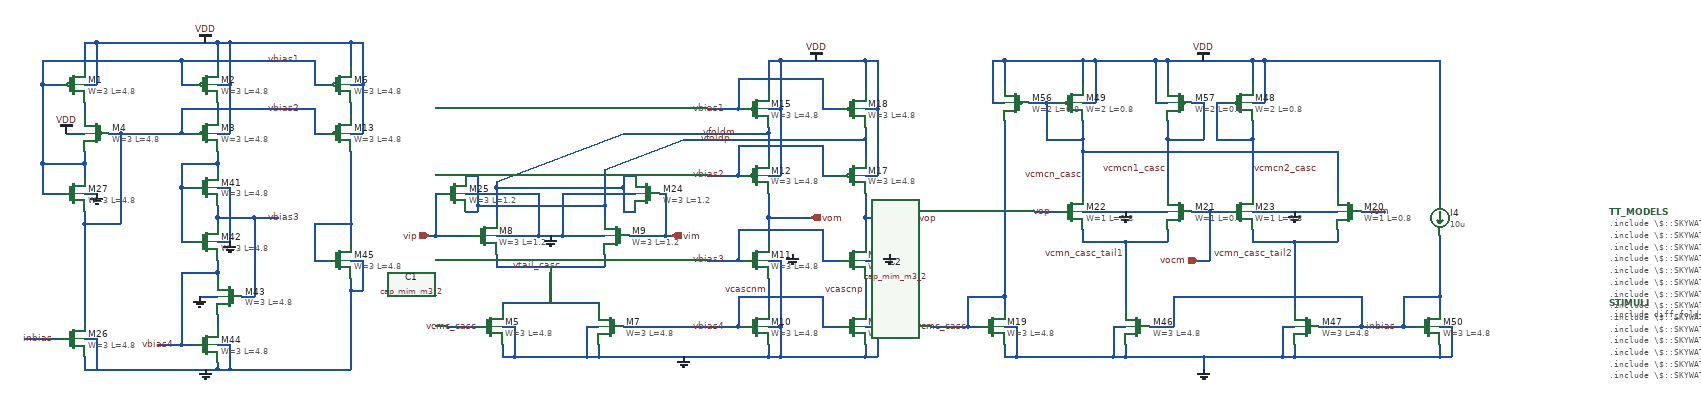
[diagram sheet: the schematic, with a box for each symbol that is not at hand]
v {xschem version=2.9.9 file_version=1.2 

* Copyright 2020 Stefan Frederik Schippers
* 
* Licensed under the Apache License, Version 2.0 (the "License");
* you may not use this file except in compliance with the License.
* You may obtain a copy of the License at
*
*     https://www.apache.org/licenses/LICENSE-2.0
*
* Unless required by applicable law or agreed to in writing, software
* distributed under the License is distributed on an "AS IS" BASIS,
* WITHOUT WARRANTIES OR CONDITIONS OF ANY KIND, either express or implied.
* See the License for the specific language governing permissions and
* limitations under the License.

}
G {}
K {}
V {}
S {}
E {}
N -510 -220 -490 -220 { lab=GND}
N -490 -220 -490 -170 { lab=GND}
N -370 -220 -350 -220 { lab=GND}
N -370 -220 -370 -170 { lab=GND}
N -510 -260 -510 -250 { lab=vtail_casc}
N -510 -260 -350 -260 { lab=vtail_casc}
N -350 -260 -350 -250 { lab=vtail_casc}
N -350 -190 -350 -170 { lab=GND}
N -510 -190 -510 -170 { lab=GND}
N -410 -370 -340 -370 { lab=GND}
N -520 -340 -520 -320 { lab=vtail_casc}
N -520 -320 -340 -320 { lab=vtail_casc}
N -340 -340 -340 -320 { lab=vtail_casc}
N -370 -170 -350 -170 { lab=GND}
N -70 -190 -70 -170 { lab=GND}
N -350 -170 -70 -170 { lab=GND}
N 90 -190 90 -170 { lab=GND}
N -50 -170 90 -170 { lab=GND}
N -70 -300 -70 -250 { lab=vcascnm}
N 90 -300 90 -250 { lab=vcascnp}
N -70 -400 -70 -360 { lab=vom}
N 90 -400 90 -360 { lab=vop}
N 90 -530 90 -500 { lab=vfoldp}
N -70 -540 -70 -500 { lab=vfoldm}
N -50 -660 90 -660 { lab=VDD}
N -70 -470 -50 -470 { lab=VDD}
N -50 -580 -50 -470 { lab=VDD}
N 90 -470 110 -470 { lab=VDD}
N 110 -580 110 -470 { lab=VDD}
N -50 -220 -50 -170 { lab=GND}
N 90 -220 110 -220 { lab=GND}
N 110 -220 110 -170 { lab=GND}
N 90 -170 110 -170 { lab=GND}
N 90 -330 110 -330 { lab=GND}
N 110 -330 110 -220 { lab=GND}
N -50 -330 -50 -220 { lab=GND}
N -120 -470 -110 -470 { lab=vbias2}
N -120 -520 -120 -470 { lab=vbias2}
N -120 -520 20 -520 { lab=vbias2}
N 20 -520 20 -470 { lab=vbias2}
N 20 -470 50 -470 { lab=vbias2}
N 90 -660 110 -660 { lab=VDD}
N 110 -660 110 -580 { lab=VDD}
N -120 -580 -110 -580 { lab=vbias1}
N -120 -630 -120 -580 { lab=vbias1}
N -120 -630 20 -630 { lab=vbias1}
N 20 -630 20 -580 { lab=vbias1}
N 20 -580 50 -580 { lab=vbias1}
N 90 -660 90 -610 { lab=VDD}
N -70 -660 -70 -610 { lab=VDD}
N -70 -330 -50 -330 { lab=GND}
N -120 -330 -110 -330 { lab=vbias3}
N -120 -380 -120 -330 { lab=vbias3}
N -120 -380 20 -380 { lab=vbias3}
N 20 -380 20 -330 { lab=vbias3}
N 20 -330 50 -330 { lab=vbias3}
N -120 -270 -120 -220 { lab=vbias4}
N -120 -270 20 -270 { lab=vbias4}
N 20 -270 20 -220 { lab=vbias4}
N 20 -220 50 -220 { lab=vbias4}
N -120 -220 -110 -220 { lab=vbias4}
N -1200 -690 -1200 -650 { lab=VDD}
N -760 -690 -760 -650 { lab=VDD}
N -980 -690 -980 -650 { lab=VDD}
N -980 -620 -960 -620 { lab=VDD}
N -960 -690 -960 -620 { lab=VDD}
N -760 -620 -740 -620 { lab=VDD}
N -740 -690 -740 -620 { lab=VDD}
N -1200 -620 -1180 -620 { lab=VDD}
N -1180 -690 -1180 -620 { lab=VDD}
N -760 -690 -740 -690 { lab=VDD}
N -980 -590 -980 -570 { lab=#net1}
N -960 -150 -760 -150 { lab=GND}
N -1270 -620 -1240 -620 { lab=vbias1}
N -1270 -440 -1240 -440 { lab=vbias1}
N -1200 -490 -1200 -470 { lab=vbias1}
N -1270 -490 -1200 -490 { lab=vbias1}
N -1270 -620 -1270 -490 { lab=vbias1}
N -1040 -540 -1020 -540 { lab=vbias2}
N -1200 -390 -1140 -390 { lab=vbias2}
N -1140 -540 -1140 -390 { lab=vbias2}
N -980 -490 -980 -480 { lab=#net2}
N -980 -400 -980 -390 { lab=vbias3}
N -980 -310 -980 -300 { lab=vbias4}
N -1040 -190 -1020 -190 { lab=vbias4}
N -920 -400 -880 -400 { lab=vbias3}
N -940 -270 -920 -270 { lab=vbias3}
N -920 -400 -920 -270 { lab=vbias3}
N -1040 -310 -1040 -190 { lab=vbias4}
N -1040 -310 -980 -310 { lab=vbias4}
N -1040 -360 -1020 -360 { lab=#net2}
N -1040 -450 -1040 -360 { lab=#net2}
N -1040 -490 -980 -490 { lab=#net2}
N -1040 -450 -1020 -450 { lab=#net2}
N -760 -590 -760 -570 { lab=#net3}
N -1040 -580 -1040 -540 { lab=vbias2}
N -760 -390 -760 -360 { lab=#net4}
N -820 -330 -800 -330 { lab=#net4}
N -820 -390 -820 -330 { lab=#net4}
N -820 -390 -760 -390 { lab=#net4}
N -1270 -660 -1270 -620 { lab=vbias1}
N -1270 -660 -1040 -660 { lab=vbias1}
N -1040 -660 -1040 -620 { lab=vbias1}
N -1040 -620 -1020 -620 { lab=vbias1}
N -1040 -660 -820 -660 { lab=vbias1}
N -820 -660 -820 -620 { lab=vbias1}
N -820 -620 -800 -620 { lab=vbias1}
N -1040 -580 -820 -580 { lab=vbias2}
N -820 -580 -820 -540 { lab=vbias2}
N -820 -540 -800 -540 { lab=vbias2}
N -1200 -590 -1200 -570 { lab=#net5}
N -980 -160 -980 -150 { lab=GND}
N -980 -190 -960 -190 { lab=GND}
N -960 -190 -960 -150 { lab=GND}
N -760 -540 -740 -540 { lab=VDD}
N -740 -620 -740 -540 { lab=VDD}
N -760 -330 -740 -330 { lab=GND}
N -740 -330 -740 -280 { lab=GND}
N -760 -280 -740 -280 { lab=GND}
N -1010 -270 -980 -270 { lab=GND}
N -980 -450 -960 -450 { lab=GND}
N -960 -450 -960 -360 { lab=GND}
N -980 -360 -960 -360 { lab=GND}
N -980 -540 -960 -540 { lab=VDD}
N -960 -620 -960 -540 { lab=VDD}
N -1230 -540 -1200 -540 { lab=VDD}
N -50 -660 -50 -580 { lab=VDD}
N -70 -220 -50 -220 { lab=GND}
N -70 -580 -50 -580 { lab=VDD}
N 90 -580 110 -580 { lab=VDD}
N 660 -410 690 -410 { lab=vocm}
N 520 -190 520 -170 { lab=GND}
N 780 -170 800 -170 { lab=GND}
N 800 -190 800 -170 { lab=GND}
N 650 -170 650 -150 { lab=GND}
N 450 -380 450 -360 { lab=vcmn_casc_tail1}
N 520 -360 590 -360 { lab=vcmn_casc_tail1}
N 590 -380 590 -360 { lab=vcmn_casc_tail1}
N 730 -380 730 -360 { lab=vcmn_casc_tail2}
N 800 -360 870 -360 { lab=vcmn_casc_tail2}
N 870 -380 870 -360 { lab=vcmn_casc_tail2}
N 670 -590 690 -590 { lab=vcmcn2_casc}
N 670 -590 670 -530 { lab=vcmcn2_casc}
N 670 -530 730 -530 { lab=vcmcn2_casc}
N 390 -590 410 -590 { lab=vcmcn_casc}
N 390 -590 390 -530 { lab=vcmcn_casc}
N 390 -530 450 -530 { lab=vcmcn_casc}
N 450 -510 450 -440 { lab=vcmcn_casc}
N 450 -590 470 -590 { lab=VDD}
N 730 -590 750 -590 { lab=VDD}
N 450 -410 590 -410 { lab=GND}
N 730 -410 870 -410 { lab=GND}
N 780 -220 800 -220 { lab=GND}
N 780 -220 780 -170 { lab=GND}
N 500 -220 520 -220 { lab=GND}
N 500 -220 500 -170 { lab=GND}
N 500 -170 520 -170 { lab=GND}
N 1040 -190 1040 -170 { lab=GND}
N 980 -270 1040 -270 { lab=vnbias_diff_ota}
N 980 -270 980 -220 { lab=vnbias_diff_ota}
N 1040 -220 1060 -220 { lab=GND}
N 1060 -220 1060 -170 { lab=GND}
N 1040 -170 1060 -170 { lab=GND}
N 980 -220 1000 -220 { lab=vnbias_diff_ota}
N 560 -220 600 -220 { lab=vnbias_diff_ota}
N 600 -270 600 -220 { lab=vnbias_diff_ota}
N 600 -270 910 -270 { lab=vnbias_diff_ota}
N 910 -270 910 -220 { lab=vnbias_diff_ota}
N 910 -410 950 -410 { lab=vom}
N 1040 -660 1040 -430 { lab=VDD}
N 750 -660 750 -590 { lab=VDD}
N 730 -660 730 -620 { lab=VDD}
N 470 -660 470 -590 { lab=VDD}
N 450 -660 450 -620 { lab=VDD}
N 1040 -270 1040 -250 { lab=vnbias_diff_ota}
N 800 -360 800 -250 { lab=vcmn_casc_tail2}
N 520 -360 520 -250 { lab=vcmn_casc_tail1}
N 320 -190 320 -170 { lab=GND}
N 260 -270 320 -270 { lab=vcmc_casc}
N 260 -270 260 -220 { lab=vcmc_casc}
N 320 -220 340 -220 { lab=GND}
N 340 -220 340 -170 { lab=GND}
N 300 -590 320 -590 { lab=VDD}
N 320 -660 320 -620 { lab=VDD}
N 300 -660 300 -590 { lab=VDD}
N 630 -590 650 -590 { lab=vcmcn1_casc}
N 650 -590 650 -530 { lab=vcmcn1_casc}
N 590 -530 650 -530 { lab=vcmcn1_casc}
N 570 -590 590 -590 { lab=VDD}
N 570 -660 570 -590 { lab=VDD}
N 590 -660 590 -620 { lab=VDD}
N 260 -220 280 -220 { lab=vcmc_casc}
N 750 -660 1040 -660 { lab=VDD}
N 340 -170 500 -170 { lab=GND}
N 200 -220 260 -220 { lab=vcmc_casc}
N 320 -270 320 -250 { lab=vcmc_casc}
N 360 -590 390 -590 { lab=vcmcn_casc}
N 730 -530 730 -440 { lab=vcmcn2_casc}
N 590 -530 590 -440 { lab=vcmcn1_casc}
N 870 -510 870 -440 { lab=vcmcn_casc}
N 450 -510 870 -510 { lab=vcmcn_casc}
N -570 -470 -550 -470 { lab=vfoldp}
N -550 -420 -550 -410 { lab=vfoldp}
N -570 -410 -550 -410 { lab=vfoldp}
N -310 -470 -290 -470 { lab=vfoldm}
N -310 -450 -310 -410 { lab=vfoldm}
N -310 -410 -290 -410 { lab=vfoldm}
N -410 -440 -290 -440 { lab=GND}
N -410 -440 -410 -370 { lab=GND}
N -570 -440 -450 -440 { lab=GND}
N -450 -440 -450 -370 { lab=GND}
N -550 -420 -340 -420 { lab=vfoldp}
N -600 -220 -550 -220 { lab=vcmc_casc}
N -300 -370 -240 -370 { lab=vim}
N -240 -440 -240 -370 { lab=vim}
N -250 -440 -240 -440 { lab=vim}
N -620 -370 -560 -370 { lab=vip}
N -620 -440 -620 -370 { lab=vip}
N -620 -440 -610 -440 { lab=vip}
N -630 -370 -620 -370 { lab=vip}
N -240 -370 -230 -370 { lab=vim}
N 640 -330 660 -330 { lab=vocm}
N 660 -410 660 -330 { lab=vocm}
N -340 -420 -340 -400 { lab=vfoldp}
N -210 -530 90 -530 { lab=vfoldp}
N -520 -450 -520 -400 { lab=vfoldm}
N -340 -480 -210 -530 { lab=vfoldp}
N -490 -170 -370 -170 { lab=GND}
N -510 -170 -490 -170 { lab=GND}
N -70 -170 -50 -170 { lab=GND}
N -170 -470 -120 -470 { lab=vbias2}
N -170 -580 -120 -580 { lab=vbias1}
N -170 -330 -120 -330 { lab=vbias3}
N -310 -220 -120 -220 { lab=vbias4}
N -960 -690 -760 -690 { lab=VDD}
N -1180 -690 -980 -690 { lab=VDD}
N -980 -690 -960 -690 { lab=VDD}
N -1200 -690 -1180 -690 { lab=VDD}
N -1200 -510 -1200 -490 { lab=vbias1}
N -1200 -410 -1200 -390 { lab=vbias2}
N -1160 -540 -1140 -540 { lab=vbias2}
N -980 -420 -980 -400 { lab=vbias3}
N -980 -400 -920 -400 { lab=vbias3}
N -1080 -190 -1040 -190 { lab=vbias4}
N -980 -330 -980 -310 { lab=vbias4}
N -980 -510 -980 -490 { lab=#net2}
N -1040 -490 -1040 -450 { lab=#net2}
N -1140 -540 -1040 -540 { lab=vbias2}
N -760 -510 -760 -390 { lab=#net4}
N -1200 -150 -980 -150 { lab=GND}
N -980 -150 -960 -150 { lab=GND}
N -760 -300 -760 -280 { lab=GND}
N -70 -660 -50 -660 { lab=VDD}
N 520 -170 650 -170 { lab=GND}
N 730 -560 730 -530 { lab=vcmcn2_casc}
N 450 -560 450 -530 { lab=vcmcn_casc}
N 650 -170 780 -170 { lab=GND}
N 800 -170 1040 -170 { lab=GND}
N 1040 -370 1040 -270 { lab=vnbias_diff_ota}
N 910 -220 980 -220 { lab=vnbias_diff_ota}
N 840 -220 910 -220 { lab=vnbias_diff_ota}
N 730 -660 750 -660 { lab=VDD}
N 590 -660 730 -660 { lab=VDD}
N 450 -660 470 -660 { lab=VDD}
N 320 -660 450 -660 { lab=VDD}
N 730 -360 800 -360 { lab=vcmn_casc_tail2}
N 450 -360 520 -360 { lab=vcmn_casc_tail1}
N 320 -170 340 -170 { lab=GND}
N 300 -660 320 -660 { lab=VDD}
N 590 -560 590 -530 { lab=vcmcn1_casc}
N 470 -660 570 -660 { lab=VDD}
N 570 -660 590 -660 { lab=VDD}
N 450 -530 450 -510 { lab=vcmcn_casc}
N -450 -370 -410 -370 { lab=GND}
N -520 -370 -450 -370 { lab=GND}
N -310 -470 -310 -450 { lab=vfoldm}
N -550 -470 -550 -420 { lab=vfoldp}
N -340 -480 -340 -420 { lab=vfoldp}
N 90 -440 90 -400 { lab=vop}
N -70 -440 -70 -400 { lab=vom}
N 630 -410 660 -410 { lab=vocm}
N 90 -550 90 -530 { lab=vfoldp}
N -70 -550 -70 -540 { lab=vfoldm}
N -520 -450 -310 -450 { lab=vfoldm}
N -520 -460 -520 -450 { lab=vfoldm}
N -520 -460 -310 -540 { lab=vfoldm}
N -310 -540 -70 -540 { lab=vfoldm}
N -70 -400 -0 -400 { lab=vom}
N 370 -410 410 -410 { lab=vop}
N 320 -560 320 -270 { lab=vcmc_casc}
N -430 -320 -430 -260 { lab=vtail_casc}
N -760 -280 -760 -150 { lab=GND}
N -980 -240 -980 -220 { lab=#net6}
N -1200 -170 -1200 -150 { lab=GND}
N -1200 -200 -1190 -200 { lab=GND}
N -1190 -200 -1180 -200 { lab=GND}
N -1180 -200 -1180 -150 { lab=GND}
N -1200 -300 -1200 -230 { lab=vbias2}
N -1200 -390 -1200 -360 { lab=vbias2}
N -1200 -440 -1180 -440 { lab=GND}
N -1270 -490 -1270 -440 { lab=vbias1}
N -1200 -360 -1200 -300 { lab=vbias2}
N 90 -400 160 -400 { lab=vop}
N -1300 -200 -1240 -200 { lab=inbias}
C {devices/title.sym} 160 -30 0 0 {name=l1 author="Nikhil Poole"}
C {devices/code.sym} 1320 -260 0 0 {name=STIMULI 
only_toplevel=true
place=end
value=".include diff_fold_casc_ota_final_commands.spice"}
C {devices/code.sym} 1320 -410 0 0 {name=TT_MODELS
only_toplevel=true
format="tcleval( @value )"
value="
.include \\\\$::SKYWATER_MODELS\\\\/cells/nfet_01v8/sky130_fd_pr__nfet_01v8__tt.corner.spice
.include \\\\$::SKYWATER_MODELS\\\\/cells/nfet_01v8_lvt/sky130_fd_pr__nfet_01v8_lvt__tt.corner.spice
.include \\\\$::SKYWATER_MODELS\\\\/cells/pfet_01v8/sky130_fd_pr__pfet_01v8__tt.corner.spice
.include \\\\$::SKYWATER_MODELS\\\\/cells/nfet_03v3_nvt/sky130_fd_pr__nfet_03v3_nvt__tt.corner.spice
.include \\\\$::SKYWATER_MODELS\\\\/cells/nfet_05v0_nvt/sky130_fd_pr__nfet_05v0_nvt__tt.corner.spice
.include \\\\$::SKYWATER_MODELS\\\\/cells/esd_nfet_01v8/sky130_fd_pr__esd_nfet_01v8__tt.corner.spice
.include \\\\$::SKYWATER_MODELS\\\\/cells/pfet_01v8_lvt/sky130_fd_pr__pfet_01v8_lvt__tt.corner.spice
.include \\\\$::SKYWATER_MODELS\\\\/cells/pfet_01v8_hvt/sky130_fd_pr__pfet_01v8_hvt__tt.corner.spice
.include \\\\$::SKYWATER_MODELS\\\\/cells/esd_pfet_g5v0d10v5/sky130_fd_pr__esd_pfet_g5v0d10v5__tt.corner.spice
.include \\\\$::SKYWATER_MODELS\\\\/cells/pfet_g5v0d10v5/sky130_fd_pr__pfet_g5v0d10v5__tt.corner.spice
.include \\\\$::SKYWATER_MODELS\\\\/cells/pfet_g5v0d16v0/sky130_fd_pr__pfet_g5v0d16v0__tt.corner.spice
.include \\\\$::SKYWATER_MODELS\\\\/cells/nfet_g5v0d10v5/sky130_fd_pr__nfet_g5v0d10v5__tt.corner.spice
.include \\\\$::SKYWATER_MODELS\\\\/cells/nfet_g5v0d16v0/sky130_fd_pr__nfet_g5v0d16v0__tt_discrete.corner.spice
.include \\\\$::SKYWATER_MODELS\\\\/cells/esd_nfet_g5v0d10v5/sky130_fd_pr__esd_nfet_g5v0d10v5__tt.corner.spice
.include \\\\$::SKYWATER_MODELS\\\\/models/corners/tt/nonfet.spice
* Mismatch parameters
.include \\\\$::SKYWATER_MODELS\\\\/cells/nfet_01v8/sky130_fd_pr__nfet_01v8__mismatch.corner.spice
.include \\\\$::SKYWATER_MODELS\\\\/cells/pfet_01v8/sky130_fd_pr__pfet_01v8__mismatch.corner.spice
.include \\\\$::SKYWATER_MODELS\\\\/cells/nfet_01v8_lvt/sky130_fd_pr__nfet_01v8_lvt__mismatch.corner.spice
.include \\\\$::SKYWATER_MODELS\\\\/cells/pfet_01v8_lvt/sky130_fd_pr__pfet_01v8_lvt__mismatch.corner.spice
.include \\\\$::SKYWATER_MODELS\\\\/cells/pfet_01v8_hvt/sky130_fd_pr__pfet_01v8_hvt__mismatch.corner.spice
.include \\\\$::SKYWATER_MODELS\\\\/cells/nfet_g5v0d10v5/sky130_fd_pr__nfet_g5v0d10v5__mismatch.corner.spice
.include \\\\$::SKYWATER_MODELS\\\\/cells/pfet_g5v0d10v5/sky130_fd_pr__pfet_g5v0d10v5__mismatch.corner.spice
.include \\\\$::SKYWATER_MODELS\\\\/cells/nfet_05v0_nvt/sky130_fd_pr__nfet_05v0_nvt__mismatch.corner.spice
.include \\\\$::SKYWATER_MODELS\\\\/cells/nfet_03v3_nvt/sky130_fd_pr__nfet_03v3_nvt__mismatch.corner.spice
* Resistor\\\\$::SKYWATER_MODELS\\\\/Capacitor
.include \\\\$::SKYWATER_MODELS\\\\/models/r+c/res_typical__cap_typical.spice
.include \\\\$::SKYWATER_MODELS\\\\/models/r+c/res_typical__cap_typical__lin.spice
* Special cells
.include \\\\$::SKYWATER_MODELS\\\\/models/corners/tt/specialized_cells.spice
* All models
.include \\\\$::SKYWATER_MODELS\\\\/models/all.spice
* Corner
.include \\\\$::SKYWATER_MODELS\\\\/models/corners/tt/rf.spice
"}
C {devices/gnd.sym} -430 -370 0 0 {name=l12 lab=GND}
C {devices/lab_wire.sym} -410 -320 0 0 {name=l17 sig_type=std_logic lab=vtail_casc}
C {devices/lab_wire.sym} -550 -220 0 0 {name=l20 sig_type=std_logic lab=vcmc_casc}
C {devices/gnd.sym} -210 -170 0 0 {name=l19 lab=GND}
C {devices/lab_wire.sym} -140 -470 0 0 {name=l21 sig_type=std_logic lab=vbias2}
C {devices/lab_wire.sym} -140 -580 0 0 {name=l22 sig_type=std_logic lab=vbias1}
C {devices/lab_wire.sym} -140 -330 0 0 {name=l24 sig_type=std_logic lab=vbias3}
C {devices/lab_wire.sym} -140 -220 0 0 {name=l25 sig_type=std_logic lab=vbias4}
C {sky130_fd_pr/nfet_01v8.sym} -1000 -450 0 0 {name=M41
L=4.8
W=3
nf=1 
mult=50
ad="'int((nf+1)/2) * W/nf * 0.29'" 
pd="'2*int((nf+1)/2) * (W/nf + 0.29)'"
as="'int((nf+2)/2) * W/nf * 0.29'" 
ps="'2*int((nf+2)/2) * (W/nf + 0.29)'"
nrd="'0.29 / W'" nrs="'0.29 / W'"
sa=0 sb=0 sd=0
model=nfet_01v8
spiceprefix=X
}
C {sky130_fd_pr/nfet_01v8.sym} -1000 -360 0 0 {name=M42
L=4.8
W=3
nf=1 
mult=2
ad="'int((nf+1)/2) * W/nf * 0.29'" 
pd="'2*int((nf+1)/2) * (W/nf + 0.29)'"
as="'int((nf+2)/2) * W/nf * 0.29'" 
ps="'2*int((nf+2)/2) * (W/nf + 0.29)'"
nrd="'0.29 / W'" nrs="'0.29 / W'"
sa=0 sb=0 sd=0
model=nfet_01v8
spiceprefix=X
}
C {sky130_fd_pr/nfet_01v8.sym} -960 -270 0 1 {name=M43
L=4.8
W=3
nf=1 
mult=18
ad="'int((nf+1)/2) * W/nf * 0.29'" 
pd="'2*int((nf+1)/2) * (W/nf + 0.29)'"
as="'int((nf+2)/2) * W/nf * 0.29'" 
ps="'2*int((nf+2)/2) * (W/nf + 0.29)'"
nrd="'0.29 / W'" nrs="'0.29 / W'"
sa=0 sb=0 sd=0
model=nfet_01v8
spiceprefix=X
}
C {sky130_fd_pr/nfet_01v8.sym} -1000 -190 0 0 {name=M44
L=4.8
W=3
nf=1 
mult=18
ad="'int((nf+1)/2) * W/nf * 0.29'" 
pd="'2*int((nf+1)/2) * (W/nf + 0.29)'"
as="'int((nf+2)/2) * W/nf * 0.29'" 
ps="'2*int((nf+2)/2) * (W/nf + 0.29)'"
nrd="'0.29 / W'" nrs="'0.29 / W'"
sa=0 sb=0 sd=0
model=nfet_01v8
spiceprefix=X
}
C {sky130_fd_pr/nfet_01v8.sym} -780 -330 0 0 {name=M45
L=4.8
W=3
nf=1
mult=1
ad="'int((nf+1)/2) * W/nf * 0.29'" 
pd="'2*int((nf+1)/2) * (W/nf + 0.29)'"
as="'int((nf+2)/2) * W/nf * 0.29'" 
ps="'2*int((nf+2)/2) * (W/nf + 0.29)'"
nrd="'0.29 / W'" nrs="'0.29 / W'"
sa=0 sb=0 sd=0
model=nfet_01v8
spiceprefix=X
}
C {devices/lab_wire.sym} -1050 -190 0 0 {name=l33 sig_type=std_logic lab=vbias4}
C {devices/lab_wire.sym} -900 -400 0 1 {name=l36 sig_type=std_logic lab=vbias3}
C {devices/lab_wire.sym} -900 -580 0 1 {name=l37 sig_type=std_logic lab=vbias2}
C {devices/lab_wire.sym} -900 -660 0 1 {name=l41 sig_type=std_logic lab=vbias1}
C {devices/gnd.sym} -1010 -270 0 0 {name=l42 lab=GND}
C {devices/gnd.sym} -960 -360 0 0 {name=l43 lab=GND}
C {devices/vdd.sym} -1000 -690 0 0 {name=l45 lab=VDD}
C {devices/gnd.sym} -1000 -150 0 0 {name=l46 lab=GND}
C {devices/vdd.sym} -1230 -540 0 0 {name=l47 lab=VDD}
C {devices/vdd.sym} 10 -660 0 0 {name=l48 lab=VDD}
C {devices/lab_wire.sym} -180 -540 0 1 {name=l55 sig_type=std_logic lab=vfoldm}
C {devices/lab_wire.sym} -130 -530 2 1 {name=l56 sig_type=std_logic lab=vfoldp}
C {devices/lab_wire.sym} -70 -280 0 0 {name=l57 sig_type=std_logic lab=vcascnm}
C {devices/lab_wire.sym} 90 -280 0 0 {name=l58 sig_type=std_logic lab=vcascnp}
C {sky130_fd_pr/nfet_01v8.sym} 540 -220 0 1 {name=M46
L=4.8
W=3
nf=1 
mult=4
ad="'int((nf+1)/2) * W/nf * 0.29'" 
pd="'2*int((nf+1)/2) * (W/nf + 0.29)'"
as="'int((nf+2)/2) * W/nf * 0.29'" 
ps="'2*int((nf+2)/2) * (W/nf + 0.29)'"
nrd="'0.29 / W'" nrs="'0.29 / W'"
sa=0 sb=0 sd=0
model=nfet_01v8
spiceprefix=X
}
C {sky130_fd_pr/nfet_01v8.sym} 820 -220 0 1 {name=M47
L=4.8
W=3
nf=1 
mult=4
ad="'int((nf+1)/2) * W/nf * 0.29'" 
pd="'2*int((nf+1)/2) * (W/nf + 0.29)'"
as="'int((nf+2)/2) * W/nf * 0.29'" 
ps="'2*int((nf+2)/2) * (W/nf + 0.29)'"
nrd="'0.29 / W'" nrs="'0.29 / W'"
sa=0 sb=0 sd=0
model=nfet_01v8
spiceprefix=X
}
C {devices/gnd.sym} 650 -150 0 0 {name=l60 lab=GND}
C {sky130_fd_pr/pfet_01v8.sym} 710 -590 0 0 {name=M48
L=0.8
W=2
nf=1
mult=8
ad="'int((nf+1)/2) * W/nf * 0.29'" 
pd="'2*int((nf+1)/2) * (W/nf + 0.29)'"
as="'int((nf+2)/2) * W/nf * 0.29'" 
ps="'2*int((nf+2)/2) * (W/nf + 0.29)'"
nrd="'0.29 / W'" nrs="'0.29 / W'"
sa=0 sb=0 sd=0
model=pfet_01v8
spiceprefix=X
}
C {sky130_fd_pr/pfet_01v8.sym} 430 -590 0 0 {name=M49
L=0.8
W=2
nf=1
mult=8
ad="'int((nf+1)/2) * W/nf * 0.29'" 
pd="'2*int((nf+1)/2) * (W/nf + 0.29)'"
as="'int((nf+2)/2) * W/nf * 0.29'" 
ps="'2*int((nf+2)/2) * (W/nf + 0.29)'"
nrd="'0.29 / W'" nrs="'0.29 / W'"
sa=0 sb=0 sd=0
model=pfet_01v8
spiceprefix=X
}
C {devices/gnd.sym} 800 -410 0 0 {name=l61 lab=GND}
C {devices/gnd.sym} 520 -410 0 0 {name=l62 lab=GND}
C {devices/isource.sym} 1040 -400 0 1 {name=I4 value=10u}
C {sky130_fd_pr/nfet_01v8.sym} 1020 -220 0 0 {name=M50
L=4.8
W=3
nf=1 
mult=4
ad="'int((nf+1)/2) * W/nf * 0.29'" 
pd="'2*int((nf+1)/2) * (W/nf + 0.29)'"
as="'int((nf+2)/2) * W/nf * 0.29'" 
ps="'2*int((nf+2)/2) * (W/nf + 0.29)'"
nrd="'0.29 / W'" nrs="'0.29 / W'"
sa=0 sb=0 sd=0
model=nfet_01v8
spiceprefix=X
}
C {devices/lab_wire.sym} 970 -220 0 0 {name=l63 sig_type=std_logic lab=inbias}
C {devices/lab_wire.sym} 590 -480 0 0 {name=l64 sig_type=std_logic lab=vcmcn1_casc}
C {devices/lab_wire.sym} 450 -470 0 0 {name=l65 sig_type=std_logic lab=vcmcn_casc}
C {devices/lab_wire.sym} 520 -340 0 0 {name=l66 sig_type=std_logic lab=vcmn_casc_tail1}
C {devices/lab_wire.sym} 800 -340 0 0 {name=l67 sig_type=std_logic lab=vcmn_casc_tail2}
C {sky130_fd_pr/pfet_01v8.sym} 340 -590 0 1 {name=M56
L=0.8
W=2
nf=1
mult=8
ad="'int((nf+1)/2) * W/nf * 0.29'" 
pd="'2*int((nf+1)/2) * (W/nf + 0.29)'"
as="'int((nf+2)/2) * W/nf * 0.29'" 
ps="'2*int((nf+2)/2) * (W/nf + 0.29)'"
nrd="'0.29 / W'" nrs="'0.29 / W'"
sa=0 sb=0 sd=0
model=pfet_01v8
spiceprefix=X
}
C {sky130_fd_pr/pfet_01v8.sym} 610 -590 0 1 {name=M57
L=0.8
W=2
nf=1
mult=8
ad="'int((nf+1)/2) * W/nf * 0.29'" 
pd="'2*int((nf+1)/2) * (W/nf + 0.29)'"
as="'int((nf+2)/2) * W/nf * 0.29'" 
ps="'2*int((nf+2)/2) * (W/nf + 0.29)'"
nrd="'0.29 / W'" nrs="'0.29 / W'"
sa=0 sb=0 sd=0
model=pfet_01v8
spiceprefix=X
}
C {devices/lab_wire.sym} 730 -480 0 1 {name=l68 sig_type=std_logic lab=vcmcn2_casc}
C {devices/vdd.sym} 650 -660 0 0 {name=l69 lab=VDD}
C {devices/lab_wire.sym} 260 -220 0 0 {name=l70 sig_type=std_logic lab=vcmc_casc}
C {devices/lab_wire.sym} 400 -410 0 0 {name=l71 sig_type=std_logic lab=vop}
C {devices/lab_wire.sym} 920 -410 0 1 {name=l72 sig_type=std_logic lab=vom}
C {sky130_fd_pr/pfet_01v8_lvt.sym} -1220 -620 0 0 {name=M1
L=4.8
W=3
nf=1
mult=6
ad="'int((nf+1)/2) * W/nf * 0.29'" 
pd="'2*int((nf+1)/2) * (W/nf + 0.29)'"
as="'int((nf+2)/2) * W/nf * 0.29'" 
ps="'2*int((nf+2)/2) * (W/nf + 0.29)'"
nrd="'0.29 / W'" nrs="'0.29 / W'"
sa=0 sb=0 sd=0
model=pfet_01v8_lvt
spiceprefix=X
}
C {sky130_fd_pr/nfet_01v8.sym} -530 -220 0 0 {name=M5
L=4.8
W=3
nf=1
mult=18
ad="'int((nf+1)/2) * W/nf * 0.29'" 
pd="'2*int((nf+1)/2) * (W/nf + 0.29)'"
as="'int((nf+2)/2) * W/nf * 0.29'" 
ps="'2*int((nf+2)/2) * (W/nf + 0.29)'"
nrd="'0.29 / W'" nrs="'0.29 / W'"
sa=0 sb=0 sd=0
model=nfet_01v8
spiceprefix=X
}
C {devices/opin.sym} 160 -400 0 0 {name=p1 lab=vop}
C {devices/opin.sym} 0 -400 0 0 {name=p2 lab=vom}
C {devices/ipin.sym} -630 -370 0 0 {name=p3 lab=vip}
C {devices/ipin.sym} -230 -370 0 1 {name=p4 lab=vim}
C {devices/ipin.sym} 640 -330 0 0 {name=p5 lab=vocm}
C {sky130_fd_pr/nfet_01v8_lvt.sym} -540 -370 0 0 {name=M8
L=1.2
W=3
nf=1
mult=18
ad="'int((nf+1)/2) * W/nf * 0.29'" 
pd="'2*int((nf+1)/2) * (W/nf + 0.29)'"
as="'int((nf+2)/2) * W/nf * 0.29'" 
ps="'2*int((nf+2)/2) * (W/nf + 0.29)'"
nrd="'0.29 / W'" nrs="'0.29 / W'"
sa=0 sb=0 sd=0
model=nfet_01v8_lvt
spiceprefix=X
}
C {sky130_fd_pr/pfet_01v8.sym} -1000 -540 0 0 {name=M3
L=4.8
W=3
nf=1
mult=6
ad="'int((nf+1)/2) * W/nf * 0.29'" 
pd="'2*int((nf+1)/2) * (W/nf + 0.29)'"
as="'int((nf+2)/2) * W/nf * 0.29'" 
ps="'2*int((nf+2)/2) * (W/nf + 0.29)'"
nrd="'0.29 / W'" nrs="'0.29 / W'"
sa=0 sb=0 sd=0
model=pfet_01v8
spiceprefix=X
}
C {sky130_fd_pr/pfet_01v8_lvt.sym} -1000 -620 0 0 {name=M2
L=4.8
W=3
nf=1
mult=6
ad="'int((nf+1)/2) * W/nf * 0.29'" 
pd="'2*int((nf+1)/2) * (W/nf + 0.29)'"
as="'int((nf+2)/2) * W/nf * 0.29'" 
ps="'2*int((nf+2)/2) * (W/nf + 0.29)'"
nrd="'0.29 / W'" nrs="'0.29 / W'"
sa=0 sb=0 sd=0
model=pfet_01v8_lvt
spiceprefix=X
}
C {sky130_fd_pr/pfet_01v8_lvt.sym} -780 -620 0 0 {name=M6
L=4.8
W=3
nf=1
mult=6
ad="'int((nf+1)/2) * W/nf * 0.29'" 
pd="'2*int((nf+1)/2) * (W/nf + 0.29)'"
as="'int((nf+2)/2) * W/nf * 0.29'" 
ps="'2*int((nf+2)/2) * (W/nf + 0.29)'"
nrd="'0.29 / W'" nrs="'0.29 / W'"
sa=0 sb=0 sd=0
model=pfet_01v8_lvt
spiceprefix=X
}
C {sky130_fd_pr/pfet_01v8.sym} -1180 -540 0 1 {name=M4
L=4.8
W=3
nf=1
mult=6
ad="'int((nf+1)/2) * W/nf * 0.29'" 
pd="'2*int((nf+1)/2) * (W/nf + 0.29)'"
as="'int((nf+2)/2) * W/nf * 0.29'" 
ps="'2*int((nf+2)/2) * (W/nf + 0.29)'"
nrd="'0.29 / W'" nrs="'0.29 / W'"
sa=0 sb=0 sd=0
model=pfet_01v8
spiceprefix=X
}
C {sky130_fd_pr/pfet_01v8.sym} -780 -540 0 0 {name=M13
L=4.8
W=3
nf=1
mult=6
ad="'int((nf+1)/2) * W/nf * 0.29'" 
pd="'2*int((nf+1)/2) * (W/nf + 0.29)'"
as="'int((nf+2)/2) * W/nf * 0.29'" 
ps="'2*int((nf+2)/2) * (W/nf + 0.29)'"
nrd="'0.29 / W'" nrs="'0.29 / W'"
sa=0 sb=0 sd=0
model=pfet_01v8
spiceprefix=X
}
C {sky130_fd_pr/nfet_01v8.sym} -330 -220 0 1 {name=M7
L=4.8
W=3
nf=1
mult=18
ad="'int((nf+1)/2) * W/nf * 0.29'" 
pd="'2*int((nf+1)/2) * (W/nf + 0.29)'"
as="'int((nf+2)/2) * W/nf * 0.29'" 
ps="'2*int((nf+2)/2) * (W/nf + 0.29)'"
nrd="'0.29 / W'" nrs="'0.29 / W'"
sa=0 sb=0 sd=0
model=nfet_01v8
spiceprefix=X
}
C {sky130_fd_pr/nfet_01v8.sym} -90 -220 0 0 {name=M10
L=4.8
W=3
nf=1
mult=18
ad="'int((nf+1)/2) * W/nf * 0.29'" 
pd="'2*int((nf+1)/2) * (W/nf + 0.29)'"
as="'int((nf+2)/2) * W/nf * 0.29'" 
ps="'2*int((nf+2)/2) * (W/nf + 0.29)'"
nrd="'0.29 / W'" nrs="'0.29 / W'"
sa=0 sb=0 sd=0
model=nfet_01v8
spiceprefix=X
}
C {sky130_fd_pr/nfet_01v8.sym} 70 -220 0 0 {name=M14
L=4.8
W=3
nf=1
mult=18
ad="'int((nf+1)/2) * W/nf * 0.29'" 
pd="'2*int((nf+1)/2) * (W/nf + 0.29)'"
as="'int((nf+2)/2) * W/nf * 0.29'" 
ps="'2*int((nf+2)/2) * (W/nf + 0.29)'"
nrd="'0.29 / W'" nrs="'0.29 / W'"
sa=0 sb=0 sd=0
model=nfet_01v8
spiceprefix=X
}
C {sky130_fd_pr/nfet_01v8.sym} -90 -330 0 0 {name=M11
L=4.8
W=3
nf=1
mult=18
ad="'int((nf+1)/2) * W/nf * 0.29'" 
pd="'2*int((nf+1)/2) * (W/nf + 0.29)'"
as="'int((nf+2)/2) * W/nf * 0.29'" 
ps="'2*int((nf+2)/2) * (W/nf + 0.29)'"
nrd="'0.29 / W'" nrs="'0.29 / W'"
sa=0 sb=0 sd=0
model=nfet_01v8
spiceprefix=X
}
C {sky130_fd_pr/nfet_01v8.sym} 70 -330 0 0 {name=M16
L=4.8
W=3
nf=1
mult=18
ad="'int((nf+1)/2) * W/nf * 0.29'" 
pd="'2*int((nf+1)/2) * (W/nf + 0.29)'"
as="'int((nf+2)/2) * W/nf * 0.29'" 
ps="'2*int((nf+2)/2) * (W/nf + 0.29)'"
nrd="'0.29 / W'" nrs="'0.29 / W'"
sa=0 sb=0 sd=0
model=nfet_01v8
spiceprefix=X
}
C {sky130_fd_pr/pfet_01v8.sym} -90 -470 0 0 {name=M12
L=4.8
W=3
nf=1
mult=6
ad="'int((nf+1)/2) * W/nf * 0.29'" 
pd="'2*int((nf+1)/2) * (W/nf + 0.29)'"
as="'int((nf+2)/2) * W/nf * 0.29'" 
ps="'2*int((nf+2)/2) * (W/nf + 0.29)'"
nrd="'0.29 / W'" nrs="'0.29 / W'"
sa=0 sb=0 sd=0
model=pfet_01v8
spiceprefix=X
}
C {sky130_fd_pr/pfet_01v8.sym} 70 -470 0 0 {name=M17
L=4.8
W=3
nf=1
mult=6
ad="'int((nf+1)/2) * W/nf * 0.29'" 
pd="'2*int((nf+1)/2) * (W/nf + 0.29)'"
as="'int((nf+2)/2) * W/nf * 0.29'" 
ps="'2*int((nf+2)/2) * (W/nf + 0.29)'"
nrd="'0.29 / W'" nrs="'0.29 / W'"
sa=0 sb=0 sd=0
model=pfet_01v8
spiceprefix=X
}
C {sky130_fd_pr/pfet_01v8_lvt.sym} -90 -580 0 0 {name=M15
L=4.8
W=3
nf=1
mult=12
ad="'int((nf+1)/2) * W/nf * 0.29'" 
pd="'2*int((nf+1)/2) * (W/nf + 0.29)'"
as="'int((nf+2)/2) * W/nf * 0.29'" 
ps="'2*int((nf+2)/2) * (W/nf + 0.29)'"
nrd="'0.29 / W'" nrs="'0.29 / W'"
sa=0 sb=0 sd=0
model=pfet_01v8_lvt
spiceprefix=X
}
C {sky130_fd_pr/pfet_01v8_lvt.sym} 70 -580 0 0 {name=M18
L=4.8
W=3
nf=1
mult=12
ad="'int((nf+1)/2) * W/nf * 0.29'" 
pd="'2*int((nf+1)/2) * (W/nf + 0.29)'"
as="'int((nf+2)/2) * W/nf * 0.29'" 
ps="'2*int((nf+2)/2) * (W/nf + 0.29)'"
nrd="'0.29 / W'" nrs="'0.29 / W'"
sa=0 sb=0 sd=0
model=pfet_01v8_lvt
spiceprefix=X
}
C {sky130_fd_pr/nfet_01v8.sym} 300 -220 0 0 {name=M19
L=4.8
W=3
nf=1
mult=18
ad="'int((nf+1)/2) * W/nf * 0.29'" 
pd="'2*int((nf+1)/2) * (W/nf + 0.29)'"
as="'int((nf+2)/2) * W/nf * 0.29'" 
ps="'2*int((nf+2)/2) * (W/nf + 0.29)'"
nrd="'0.29 / W'" nrs="'0.29 / W'"
sa=0 sb=0 sd=0
model=nfet_01v8
spiceprefix=X
}
C {sky130_fd_pr/nfet_01v8_lvt.sym} 890 -410 0 1 {name=M20
L=0.8
W=1
nf=1
mult=4
ad="'int((nf+1)/2) * W/nf * 0.29'" 
pd="'2*int((nf+1)/2) * (W/nf + 0.29)'"
as="'int((nf+2)/2) * W/nf * 0.29'" 
ps="'2*int((nf+2)/2) * (W/nf + 0.29)'"
nrd="'0.29 / W'" nrs="'0.29 / W'"
sa=0 sb=0 sd=0
model=nfet_01v8_lvt
spiceprefix=X
}
C {sky130_fd_pr/nfet_01v8_lvt.sym} -320 -370 0 1 {name=M9
L=1.2
W=3
nf=1
mult=18
ad="'int((nf+1)/2) * W/nf * 0.29'" 
pd="'2*int((nf+1)/2) * (W/nf + 0.29)'"
as="'int((nf+2)/2) * W/nf * 0.29'" 
ps="'2*int((nf+2)/2) * (W/nf + 0.29)'"
nrd="'0.29 / W'" nrs="'0.29 / W'"
sa=0 sb=0 sd=0
model=nfet_01v8_lvt
spiceprefix=X
}
C {sky130_fd_pr/nfet_01v8_lvt.sym} -270 -440 0 1 {name=M24
L=1.2
W=3
nf=1
mult=18
ad="'int((nf+1)/2) * W/nf * 0.29'" 
pd="'2*int((nf+1)/2) * (W/nf + 0.29)'"
as="'int((nf+2)/2) * W/nf * 0.29'" 
ps="'2*int((nf+2)/2) * (W/nf + 0.29)'"
nrd="'0.29 / W'" nrs="'0.29 / W'"
sa=0 sb=0 sd=0
model=nfet_01v8_lvt
spiceprefix=X
}
C {sky130_fd_pr/nfet_01v8_lvt.sym} -590 -440 0 0 {name=M25
L=1.2
W=3
nf=1
mult=18
ad="'int((nf+1)/2) * W/nf * 0.29'" 
pd="'2*int((nf+1)/2) * (W/nf + 0.29)'"
as="'int((nf+2)/2) * W/nf * 0.29'" 
ps="'2*int((nf+2)/2) * (W/nf + 0.29)'"
nrd="'0.29 / W'" nrs="'0.29 / W'"
sa=0 sb=0 sd=0
model=nfet_01v8_lvt
spiceprefix=X
}
C {sky130_fd_pr/nfet_01v8.sym} -1220 -200 0 0 {name=M26
L=4.8
W=3
nf=1 
mult=4
ad="'int((nf+1)/2) * W/nf * 0.29'" 
pd="'2*int((nf+1)/2) * (W/nf + 0.29)'"
as="'int((nf+2)/2) * W/nf * 0.29'" 
ps="'2*int((nf+2)/2) * (W/nf + 0.29)'"
nrd="'0.29 / W'" nrs="'0.29 / W'"
sa=0 sb=0 sd=0
model=nfet_01v8
spiceprefix=X
}
C {devices/gnd.sym} -1180 -440 0 0 {name=l5 lab=GND}
C {sky130_fd_pr/nfet_01v8_lvt.sym} -1220 -440 0 0 {name=M27
L=4.8
W=3
nf=1
mult=56
ad="'int((nf+1)/2) * W/nf * 0.29'" 
pd="'2*int((nf+1)/2) * (W/nf + 0.29)'"
as="'int((nf+2)/2) * W/nf * 0.29'" 
ps="'2*int((nf+2)/2) * (W/nf + 0.29)'"
nrd="'0.29 / W'" nrs="'0.29 / W'"
sa=0 sb=0 sd=0
model=nfet_01v8_lvt
spiceprefix=X
}
C {devices/lab_wire.sym} -1250 -200 0 0 {name=l2 sig_type=std_logic lab=inbias}
C {sky130_fd_pr/cap_mim_m3_2.sym} 130 -370 0 0 {name=C2 model=cap_mim_m3_2 W=10 L=10 MF=8 spiceprefix=X}
C {devices/gnd.sym} 130 -340 0 0 {name=l6 lab=GND}
C {sky130_fd_pr/cap_mim_m3_2.sym} -30 -370 0 0 {name=C1 model=cap_mim_m3_2 W=10 L=10 MF=8 spiceprefix=X}
C {devices/gnd.sym} -30 -340 0 0 {name=l7 lab=GND}
C {sky130_fd_pr/nfet_01v8_lvt.sym} 610 -410 0 1 {name=M21
L=0.8
W=1
nf=1
mult=4
ad="'int((nf+1)/2) * W/nf * 0.29'" 
pd="'2*int((nf+1)/2) * (W/nf + 0.29)'"
as="'int((nf+2)/2) * W/nf * 0.29'" 
ps="'2*int((nf+2)/2) * (W/nf + 0.29)'"
nrd="'0.29 / W'" nrs="'0.29 / W'"
sa=0 sb=0 sd=0
model=nfet_01v8_lvt
spiceprefix=X
}
C {sky130_fd_pr/nfet_01v8_lvt.sym} 430 -410 0 0 {name=M22
L=0.8
W=1
nf=1
mult=4
ad="'int((nf+1)/2) * W/nf * 0.29'" 
pd="'2*int((nf+1)/2) * (W/nf + 0.29)'"
as="'int((nf+2)/2) * W/nf * 0.29'" 
ps="'2*int((nf+2)/2) * (W/nf + 0.29)'"
nrd="'0.29 / W'" nrs="'0.29 / W'"
sa=0 sb=0 sd=0
model=nfet_01v8_lvt
spiceprefix=X
}
C {sky130_fd_pr/nfet_01v8_lvt.sym} 710 -410 0 0 {name=M23
L=0.8
W=1
nf=1
mult=4
ad="'int((nf+1)/2) * W/nf * 0.29'" 
pd="'2*int((nf+1)/2) * (W/nf + 0.29)'"
as="'int((nf+2)/2) * W/nf * 0.29'" 
ps="'2*int((nf+2)/2) * (W/nf + 0.29)'"
nrd="'0.29 / W'" nrs="'0.29 / W'"
sa=0 sb=0 sd=0
model=nfet_01v8_lvt
spiceprefix=X
}
